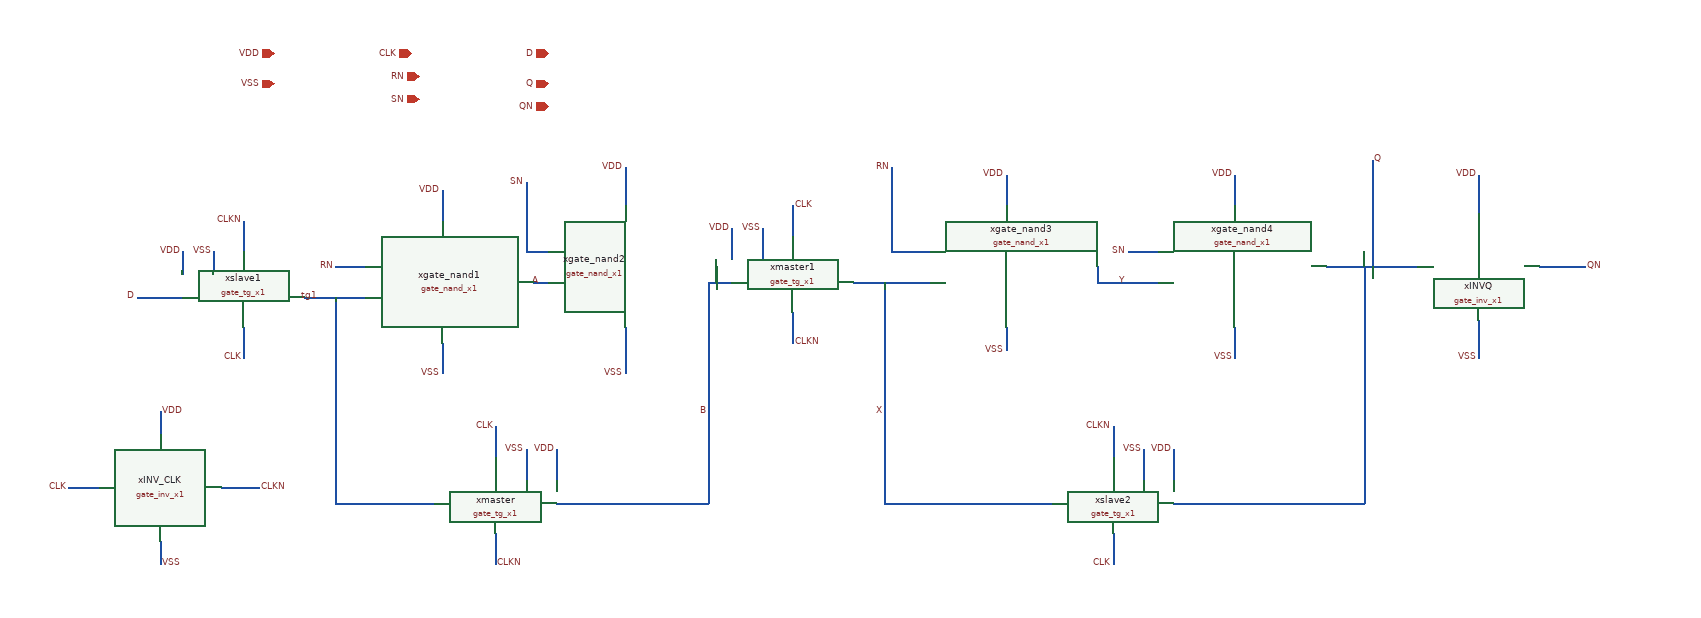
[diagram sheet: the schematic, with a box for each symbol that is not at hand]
v {xschem version=3.4.8RC file_version=1.3}
G {}
K {}
V {}
S {}
F {}
E {}
N 410 -410 470 -410 {lab=tg1}
N 250 -470 250 -440 {lab=VDD}
N 290 -470 290 -440 {lab=VSS}
N 330 -510 330 -470 {lab=CLKN}
N 330 -370 330 -330 {lab=CLK}
N 450 -450 490 -450 {lab=RN}
N 470 -410 490 -410 {lab=tg1}
N 590 -550 590 -510 {lab=VDD}
N 590 -350 590 -310 {lab=VSS}
N 450 -410 450 -230 {lab=tg1}
N 450 -180 450 -140 {lab=tg1}
N 450 -230 450 -180 {lab=tg1}
N 1050 -390 1050 -350 {lab=CLKN}
N 1050 -530 1050 -490 {lab=CLK}
N 1010 -500 1010 -460 {lab=VSS}
N 970 -500 970 -460 {lab=VDD}
N 660 -240 660 -200 {lab=CLK}
N 700 -210 700 -170 {lab=VSS}
N 740 -210 740 -170 {lab=VDD}
N 660 -100 660 -60 {lab=CLKN}
N 1130 -430 1210 -430 {lab=X}
N 1490 -470 1530 -470 {lab=SN}
N 1550 -210 1550 -170 {lab=VDD}
N 1510 -210 1510 -170 {lab=VSS}
N 1470 -240 1470 -200 {lab=CLKN}
N 1470 -100 1470 -60 {lab=CLK}
N 1750 -450 1850 -450 {lab=Q}
N 1800 -450 1800 -140 {lab=Q}
N 1170 -430 1170 -140 {lab=X}
N 1170 -140 1310 -140 {lab=X}
N 1630 -370 1630 -330 {lab=VSS}
N 1630 -570 1630 -530 {lab=VDD}
N 1950 -570 1950 -530 {lab=VDD}
N 1950 -370 1950 -330 {lab=VSS}
N 2050 -450 2090 -450 {lab=QN}
N 190 -410 250 -410 {lab=D}
N 220 -90 220 -60 {lab=VSS}
N 220 -260 220 -230 {lab=VDD}
N 300 -160 350 -160 {lab=CLKN}
N 100 -160 140 -160 {lab=CLK}
N 1950 -530 1950 -520 {lab=VDD}
N 2030 -450 2050 -450 {lab=QN}
N 1850 -450 1870 -450 {lab=Q}
N 1950 -380 1950 -370 {lab=VSS}
N 910 -140 940 -140 {lab=B}
N 940 -430 940 -140 {lab=B}
N 740 -140 910 -140 {lab=B}
N 450 -140 580 -140 {lab=tg1}
N 1310 -140 1390 -140 {lab=X}
N 1550 -140 1800 -140 {lab=Q}
N 1810 -590 1810 -450 {lab=Q}
N 710 -430 730 -430 {lab=A}
N 940 -430 970 -430 {lab=B}
N 950 -450 950 -430 {lab=B}
N 700 -470 730 -470 {lab=SN}
N 700 -560 700 -470 {lab=SN}
N 830 -580 830 -530 {lab=VDD}
N 830 -370 830 -310 {lab=VSS}
N 1210 -430 1230 -430 {lab=X}
N 1450 -430 1530 -430 {lab=Y}
N 1450 -450 1450 -430 {lab=Y}
N 1330 -370 1330 -340 {lab=VSS}
N 1330 -570 1330 -530 {lab=VDD}
N 1180 -470 1230 -470 {lab=RN}
N 1180 -580 1180 -470 {lab=RN}
C {iopin.sym} 370 -730 0 0 {name=p1 lab=VDD}
C {iopin.sym} 370 -690 0 0 {name=p3 lab=VSS}
C {iopin.sym} 550 -730 0 0 {name=p5 lab=CLK
}
C {iopin.sym} 730 -730 0 0 {name=p9 lab=D}
C {iopin.sym} 560 -700 0 0 {name=p13 lab=RN}
C {lab_pin.sym} 590 -550 0 0 {name=p15 sig_type=std_logic lab=VDD}
C {lab_pin.sym} 970 -500 1 0 {name=p16 sig_type=std_logic lab=VDD}
C {lab_pin.sym} 250 -470 1 0 {name=p17 sig_type=std_logic lab=VDD}
C {lab_pin.sym} 740 -210 3 1 {name=p18 sig_type=std_logic lab=VDD}
C {lab_pin.sym} 1550 -210 3 1 {name=p19 sig_type=std_logic lab=VDD}
C {lab_pin.sym} 1630 -570 0 0 {name=p22 sig_type=std_logic lab=VDD}
C {lab_pin.sym} 1950 -570 0 0 {name=p23 sig_type=std_logic lab=VDD}
C {lab_pin.sym} 290 -470 3 1 {name=p24 sig_type=std_logic lab=VSS}
C {lab_pin.sym} 1010 -500 3 1 {name=p25 sig_type=std_logic lab=VSS}
C {lab_pin.sym} 700 -210 1 0 {name=p26 sig_type=std_logic lab=VSS}
C {lab_pin.sym} 1510 -210 1 0 {name=p27 sig_type=std_logic lab=VSS}
C {lab_pin.sym} 590 -310 2 1 {name=p29 sig_type=std_logic lab=VSS}
C {lab_pin.sym} 1630 -330 2 1 {name=p31 sig_type=std_logic lab=VSS}
C {lab_pin.sym} 1950 -330 2 1 {name=p32 sig_type=std_logic lab=VSS}
C {lab_pin.sym} 450 -450 0 0 {name=p33 sig_type=std_logic lab=RN}
C {lab_pin.sym} 1180 -580 0 0 {name=p34 sig_type=std_logic lab=RN}
C {lab_pin.sym} 190 -410 0 0 {name=p36 sig_type=std_logic lab=D
}
C {lab_pin.sym} 330 -330 1 1 {name=p37 sig_type=std_logic lab=CLK
}
C {lab_pin.sym} 1470 -60 3 0 {name=p40 sig_type=std_logic lab=CLK
}
C {lab_pin.sym} 330 -510 1 0 {name=p41 sig_type=std_logic lab=CLKN
}
C {lab_pin.sym} 1470 -240 3 1 {name=p43 sig_type=std_logic lab=CLKN
}
C {designs/sar_adc/digital/gate_tg_x1/xschem/gate_tg_x1.sym} 330 -390 0 0 {name=xslave1}
C {designs/sar_adc/digital/gate_tg_x1/xschem/gate_tg_x1.sym} 1470 -120 0 1 {name=xslave2}
C {designs/sar_adc/digital/gate_tg_x1/xschem/gate_tg_x1.sym} 660 -120 0 1 {name=xmaster}
C {lab_pin.sym} 350 -160 0 1 {name=p7 sig_type=std_logic lab=CLKN
}
C {lab_pin.sym} 220 -260 2 0 {name=p14 sig_type=std_logic lab=VDD}
C {lab_pin.sym} 220 -60 0 1 {name=p47 sig_type=std_logic lab=VSS}
C {lab_pin.sym} 100 -160 2 1 {name=p49 sig_type=std_logic lab=CLK
}
C {lab_pin.sym} 430 -410 1 1 {name=p51 sig_type=std_logic lab=tg1}
C {iopin.sym} 730 -690 0 0 {name=p6 lab=Q}
C {iopin.sym} 730 -660 0 0 {name=p35 lab=QN}
C {lab_pin.sym} 1810 -590 0 1 {name=p11 sig_type=std_logic lab=Q}
C {lab_pin.sym} 2090 -450 2 0 {name=p52 sig_type=std_logic lab=QN}
C {lab_pin.sym} 830 -580 0 0 {name=p20 sig_type=std_logic lab=VDD}
C {lab_pin.sym} 830 -310 2 1 {name=p28 sig_type=std_logic lab=VSS}
C {lab_pin.sym} 1330 -340 2 1 {name=p21 sig_type=std_logic lab=VSS}
C {lab_pin.sym} 1330 -570 0 0 {name=p30 sig_type=std_logic lab=VDD}
C {iopin.sym} 560 -670 0 0 {name=p50 lab=SN}
C {lab_pin.sym} 700 -560 0 0 {name=p53 sig_type=std_logic lab=SN}
C {lab_pin.sym} 1490 -470 0 0 {name=p54 sig_type=std_logic lab=SN}
C {lab_pin.sym} 720 -430 1 1 {name=p55 sig_type=std_logic lab=A}
C {lab_pin.sym} 940 -260 2 1 {name=p56 sig_type=std_logic lab=B}
C {lab_pin.sym} 1170 -260 2 1 {name=p57 sig_type=std_logic lab=X}
C {lab_pin.sym} 1490 -430 1 1 {name=p58 sig_type=std_logic lab=Y}
C {lab_pin.sym} 660 -240 0 0 {name=p2 sig_type=std_logic lab=CLK
}
C {lab_pin.sym} 1050 -530 2 0 {name=p4 sig_type=std_logic lab=CLK
}
C {lab_pin.sym} 660 -60 0 1 {name=p8 sig_type=std_logic lab=CLKN
}
C {lab_pin.sym} 1050 -350 0 1 {name=p10 sig_type=std_logic lab=CLKN
}
C {designs/sar_adc/digital/gate_tg_x1/xschem/gate_tg_x1.sym} 1050 -410 0 0 {name=xmaster1}
C {designs/sar_adc/digital/gate_inv_x1/xschem/gate_inv_x1.sym} 240 -140 0 0 {name=xINV_CLK}
C {designs/sar_adc/digital/gate_nand_x1/xschem/gate_nand_x1.sym} 590 -430 0 0 {name=xgate_nand1}
C {designs/sar_adc/digital/gate_nand_x1/xschem/gate_nand_x1.sym} 830 -450 0 0 {name=xgate_nand2}
C {designs/sar_adc/digital/gate_nand_x1/xschem/gate_nand_x1.sym} 1330 -450 0 0 {name=xgate_nand3}
C {designs/sar_adc/digital/gate_nand_x1/xschem/gate_nand_x1.sym} 1630 -450 0 0 {name=xgate_nand4}
C {designs/sar_adc/digital/gate_inv_x1/xschem/gate_inv_x1.sym} 1970 -430 0 0 {name=xINVQ}
